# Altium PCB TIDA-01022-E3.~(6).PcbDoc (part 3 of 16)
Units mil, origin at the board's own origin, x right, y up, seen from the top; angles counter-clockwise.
Board outline 6929.13 x 11614.17 mil, 12 copper layers (L1_Top Layer, L2_GND, L3_GND, L4_Signal Layer 1, L5_GND, L6_PWR, L7_GND/PWR, L8_PWR, L9_GND/PWR, L10_Signal Layer 2, L11_GND, L12_Bottom Layer), stack 64.6 mil thick; 1733 components, 993 nets, 5987 pads, 3555 vias.

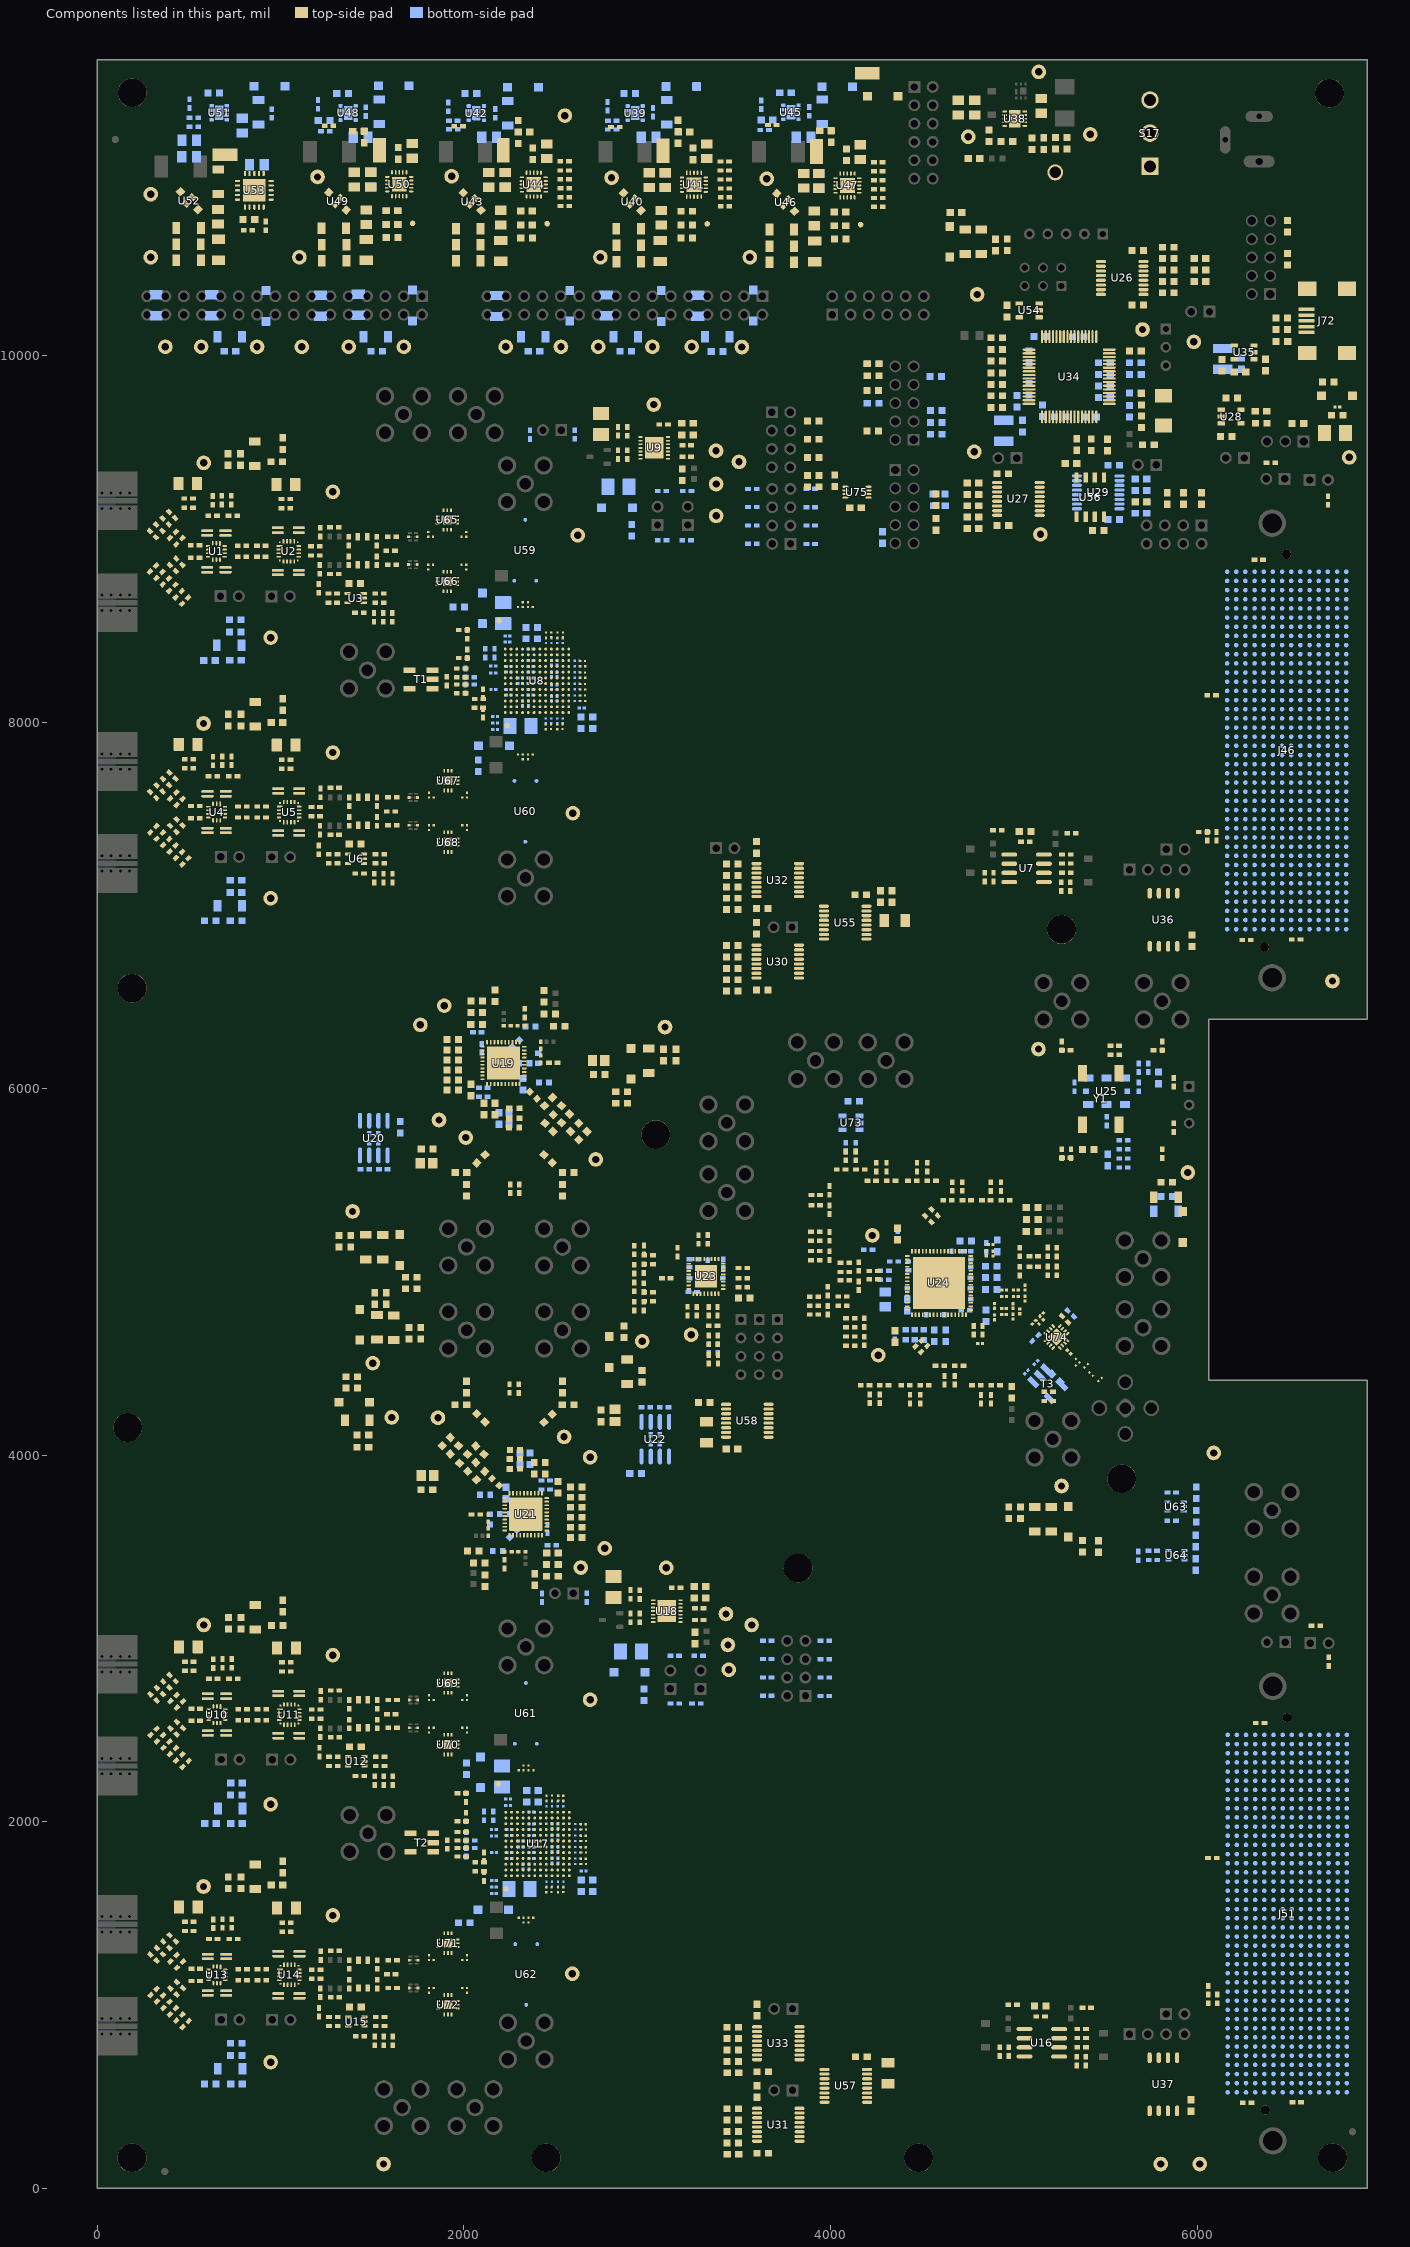
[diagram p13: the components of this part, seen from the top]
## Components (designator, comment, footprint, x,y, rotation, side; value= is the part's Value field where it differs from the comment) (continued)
R246 "CRCW04020000Z0ED" 0402#1 3103.5,4965.79 r180 top
R247 "CRCW04020000Z0ED" 0402#1 3521.5,4966.29 r0 top
R248 "CRCW04020000Z0ED" 0402#1 3521.5,5021.29 r0 top
R249 "CRCW04020000Z0ED" 0402#1 3279.5,5176.79 r90 top
R250 "CRCW04020000Z0ED" 0402#1 3330.5,5177.29 r90 top
R251 "CRCW04020000Z0ED" 0402#1 3270.5,4785.29 r270 top
R252 "CRCW04020000Z0ED" 0402#1 2982,5120.29 r90 top
R253 "CRCW04020000Z0ED" 0402#1 3335.5,4582.04 r90 bottom
R254 "CRCW04020000Z0ED" 0402#1 3007,5091.58 r180 top
R255 "CRCW04020000Z0ED" 0402#2 3105,5039.58 r180 top
R256 "CRCW04020000Z0ED" 0402#1 2981,5018.29 r270 top
R257 "CRCW04020000Z0ED" 0402#1 3384.5,4582.04 r90 bottom
R258 "CRCW0402160RJNED" 0402#1 2929.5,5015.79 r90 top
R259 "CRCW0402160RJNED" 0402#1 2929.5,5119.79 r270 top
R260 "CRCW04020000Z0ED" 0402#1 2981,4914.29 r90 top
R261 "CRCW04020000Z0ED" 0402#1 3335.75,4523.54 r90 top
R262 "CRCW04020000Z0ED" 0402#1 3007,4889.29 r180 top
R263 "CRCW04020000Z0ED" 0402#1 3335.5,4629.29 r90 top
R264 "CRCW04020000Z0ED" 0402#1 3007,4840.29 r180 top
R265 "CRCW04020000Z0ED" 0402#1 2980,4813.29 r270 top
R266 "CRCW04020000Z0ED" 0402#1 3385.75,4523.54 r90 top
R267 "CRCW0402100RFKED" 0402#1 3359.5,4707.29 r180 top
R268 "CRCW0402160RJNED" 0402#1 2929,4813.29 r90 top
R269 "CRCW0402160RJNED" 0402#1 2929,4918.29 r270 top
R270 "CRCW04020000Z0ED" 0402#1 3384.5,4629.29 r90 top
R271 "CRCW04020000Z0ED" 0402#1 3917.47,5219.44 r180 top
R272 "CRCW04020000Z0ED" 0402#1 3917.47,5064.44 r0 top
R273 "CRCW0402120RJNED" 0402#1 3993.95,5088.99 r90 top
R274 "CRCW0402120RJNED" 0402#1 3993.95,5193.99 r270 top
R275 "RC0201FR-07620RL" 0201#1 4873.47,5150.94 r0 top
R276 "CRCW0402120RJNED" 0402#1 4234.41,5004.77 r0 top
R277 "CRCW04020000Z0ED" 0402#1 4078.41,4999.77 r180 top
R278 "CRCW02010000Z0ED" 0201#1 5011.41,4866.77 r180 top
R279 "CRCW0402120RJNED" 0402#1 4234.41,4959.77 r0 top
R280 "CRCW04020000Z0ED" 0402#1 4078.41,4954.77 r180 top
R281 "RC0201JR-0751RL" 0201#1 5060.97,4854.02 r90 top
R282 "CRCW0402120RJNED" 0402#1 4154.41,5029.77 r270 top
R283 "CRCW0402120RJNED" 0402#1 4154.41,4924.77 r90 top
R284 "RC0201FR-0739KL" 0201#1 4815.97,4610.02 r0 top
R285 "CRCW04020000Z0ED" 0402#1 4078.41,5049.77 r180 top
R286 "CRCW04020000Z0ED" 0402#1 4108.01,4748.08 r180 top
R287 "CRCW04020000Z0ED" 0402#1 4108.01,4598.08 r0 top
R288 "CRCW0402120RJNED" 0402#1 4184.01,4623.08 r90 top
R289 "CRCW0402120RJNED" 0402#1 4184.01,4723.08 r270 top
R290 "CRCW02010000Z0ED" 0201#1 5011.41,4900.77 r180 top
R291 "RC0201JR-0751RL" 0201#1 5060.97,4914.02 r270 top
R292 "CRCW0402120RJNED" 0402#1 4065.03,4865.77 r0 top
R293 "CRCW04020000Z0ED" 0402#1 3909.47,4865.44 r180 top
R294 "CRCW0402120RJNED" 0402#1 4065.03,4815.77 r0 top
R295 "CRCW04020000Z0ED" 0402#1 3909.47,4815.44 r180 top
R296 "CRCW06030000Z0EA" 0603 5229.19,4421.27 r135 bottom
R297 "CRCW020149R9FKED" 0201#1 5121,4506 r45 bottom
R298 "CRCW020149R9FKED" 0201#1 4996,4756 r270 top
R299 "CRCW0402120RJNED" 0402#1 3985.03,4895.77 r270 top
R300 "CRCW0402120RJNED" 0402#1 3985.03,4790.77 r90 top
R301 "CRCW02010000Z0ED" 0201_adc 5421.69,4442.69 r135 top
R302 "CRCW02010000Z0ED" 0201#1 5109.57,4725.5 r45 top
R303 "CRCW04020000Z0ED" 0402#1 3909.47,4768.19 r180 top
R304 "CRCW04020000Z0ED" 0402#1 4433.63,4306.29 r270 top
R305 "ERJ-1GEF1000C" 0201#1 5032,4785 r270 top
R306 "CRCW04020000Z0ED" 0402#1 4488.63,4306.29 r270 top
R307 "RC0201FR-07294RL" 0201_adc 5470.19,4413.19 r225 top
R308 "RC0201FR-07294RL" 0201_adc 5394.19,4488.19 r225 top
R309 "CRCW02010000Z0ED" 0201#1 5151.27,4767.21 r225 top
R310 "CRCW04020000Z0ED" 0402#1 4621.63,4408.95 r270 top
R311 "CRCW020149R9FKED" 0201#1 5068,4454 r225 bottom
R312 "CRCW020149R9FKED" 0201#1 4996,4814 r270 top
R313 "CRCW04020000Z0ED" 0402#1 4676.63,4408.95 r270 top
R314 "CRCW04020000Z0ED" 0402#1 4820.47,4305.32 r270 top
R315 "CRCW04020000Z0ED" 0402#1 4875.47,4305.32 r270 top
R316 "CRCW04020000Z0ED" 0402#1 4717.97,5465.94 r90 top
R317 "CRCW04020000Z0ED" 0402#1 4662.97,5465.94 r90 top
R318 "CRCW04020000Z0ED" 0402#1 4929.41,5465.26 r90 top
R319 "CRCW040249R9FKED" 0402#1 5185.67,5005.53 r90 top
R320 "CRCW04020000Z0ED" 0402#1 4874.41,5465.26 r90 top
R321 "CRCW0402130RFKED" 0402#1 5234.67,5005.53 r90 top
R322 "CRCW04020000Z0ED" 0402#1 4526.62,5572.16 r90 top
R323 "CRCW04020000Z0ED" 0402#1 5809.06,6233.44 r90 top
R324 "CRCW040218R0JNED" 0402#1 5809.09,5645.89 r270 top
R325 "CRCW04020000Z0ED" 0402#1 4471.62,5572.16 r90 top
R326 "CRCW04020000Z0ED" 0402#1 5262.04,6233.44 r90 top
R327 "CRCW040218R0JNED" 0402#1 5262.08,5645.89 r270 top
R328 "CRCW0402240RJNED" 0402#1 4446.62,5497.16 r0 top
R329 "CRCW0402240RJNED" 0402#1 4551.62,5497.16 r180 top
R330 "CRCW0402240RJNED" 0402#1 4849.41,5390.26 r0 top
R331 "CRCW0402240RJNED" 0402#1 4954.41,5390.26 r180 top
R332 "CRCW0402240RJNED" 0402#1 4638,5390.5 r0 top
R333 "CRCW0402240RJNED" 0402#1 4743,5390.5 r180 top
R334 "CRCW0402240RJNED" 0402#1 4900.48,4381.19 r180 top
R335 "CRCW0402240RJNED" 0402#1 4795.48,4381.19 r0 top
R336 "CRCW0402240RJNED" 0402#1 4701.63,4488.95 r180 top
R337 "CRCW0402240RJNED" 0402#1 4596.63,4488.95 r0 top
R338 "CRCW0402240RJNED" 0402#1 4512.25,4382.29 r180 top
R339 "CRCW0402240RJNED" 0402#1 4408.63,4382.29 r0 top
R340 "CRCW0402130RFKED" 0402#1 5234.67,5108.53 r270 top
R341 "CRCW040249R9FKED" 0402#1 5185.67,5109.24 r270 top
R342 "CRCW040220R0FKED" 0402#1 4479.64,4610.21 r45 top
R343 "CRCW04020000Z0ED" 0402#1 4212.97,4308.02 r270 top
R344 "CRCW0402100RFKED" 0402#1 5311.63,5645.1 r90 top
R345 "CRCW040220R0FKED" 0402#1 4510.77,4580.16 r45 top
R346 "CRCW04020000Z0ED" 0402#1 4267.97,4308.02 r270 top
R347 "CRCW0402220RJNED" 0402#1 4292.44,4382.29 r180 top
R348 "CRCW0402220RJNED" 0402#1 4187.97,4382.29 r0 top
R349 "CRCW040220R0FKED" 0402#1 4567.97,5324.02 r315 top
R350 "CRCW04020000Z0ED" 0402#1 4304.86,5571.99 r90 top
R351 "RC0603FR-0782RL" 0603 5406.13,5668.6 r180 top
R352 "CRCW04021K20JNED" 0402#1 5330.97,6009.84 r90 bottom
R353 "CRCW04021K20JNED" 0402#1 5680.97,6009.84 r90 bottom
R354 "CRCW040220R0FKED" 0402#1 4532.97,5289.02 r315 top
R355 "CRCW04020000Z0ED" 0402#1 4249.86,5571.99 r90 top
R356 "CRCW04020000Z0ED" 0402#1 5285.66,6209.82 r180 top
R357 "CRCW04020000Z0ED" 0402#1 5785.44,6209.82 r0 top
R358 "CRCW04021K20JNED" 0402#1 5505.97,5822.49 r90 bottom
R359 "CRCW04020000Z0ED" 0402#1 5550.5,6233.95 r180 top
R360 "CRCW04020000Z0ED" 0402#1 4137.62,5633.5 r90 top
R361 "CRCW04020000Z0ED" 0402#1 4082.62,5633.5 r90 top
R362 "CRCW0402240RJNED" 0402#1 4057.62,5558.5 r0 top
R363 "CRCW0402240RJNED" 0402#1 4162.62,5558.5 r180 top
R364 "CRCW0402240RJNED" 0402#1 3994.28,5339.5 r90 top
R365 "CRCW0402240RJNED" 0402#1 3994.28,5444.5 r270 top
R366 "CRCW0402220RJNED" 0402#1 4224.86,5496.99 r0 top
R367 "CRCW0402220RJNED" 0402#1 4329.86,5496.99 r180 top
R368 "ERJ-2RKF1002X" 0402#1 4448.66,5008.62 r180 bottom
R369 "CRCW040247R0JNED" 0402#1 4294.09,4956.94 r0 bottom
R370 "CRCW0603750RFKEA" 0603 5099.49,5352.39 r0 top
R371 "CRCW0603750RFKEA" 0603 5101.03,5286.39 r0 top
R372 "CRCW0603750RFKEA" 0603 4988.39,4342.97 r270 top
R373 "CRCW0603750RFKEA" 0603 5099.47,5220.14 r0 top
R374 "CRCW06030000Z0EA" 0603 4576,9078.5 r270 top
R375 "CRCW06030000Z0EA" 0603 6015.28,10528.12 r0 top
R376 "CRCW06030000Z0EA" 0603 4593.57,9180.1 r180 bottom
R377 "CRCW06030000Z0EA" 0603 6015.28,10466.05 r0 top
R378 "CRCW06030000Z0EA" 0603 4592,9244 r180 bottom
R379 "CRCW06030000Z0EA" 0603 6015.5,10403 r0 top
R380 "CRCW060310K0JNEA" 0603 6549.5,9629.5 r0 top
R381 "CRCW060310K0JNEA" 0603 6024,9220 r270 top
R382 "CRCW060310K0JNEA" 0603 6348,9696 r0 top
R383 "CRCW060310K0JNEA" 0603 5925,9220 r270 top
R384 "CRCW060310K0JNEA" 0603 5837,9220 r270 top
R385 "CRCW060310K0JNEA" 0603 5694.63,9202.01 r0 top
R386 "CRCW06030000Z0EA" 0603 3199.95,11220.04 r0 top
R387 "CRCW06030000Z0EA" 0603 3168.46,11251.53 r270 top
R388 "CRCW06030000Z0EA" 0603 2327.5,11219.5 r0 top
R389 "CRCW06030000Z0EA" 0603 2296,11250.99 r270 top
R390 "CRCW04020000Z0ED" 0402#1 4137.62,5680.75 r90 bottom
R391 "CRCW04020000Z0ED" 0402#1 4082.62,5680.75 r90 bottom
R392 "CRCW02010000Z0ED" 0201_ADC 5348,4497.63 r225 top
R393 "CRCW040233K0JNED" 0402#1 5189.54,4296.24 r180 top
R394 "RC0603FR-07100RL" 0603 5842.35,10528.12 r0 top
R395 "ERJ-1GN0R00C" 0201#1 5151.27,4748.84 r315 top
R396 "RC0603FR-07100RL" 0603 5842.35,10466.12 r0 top
R397 "CRCW0402100KFKED" 0402#1 5189.73,4347 r180 top
R398 "RC0603FR-07100RL" 0603 5842.35,10404.12 r0 top
R399 "ERJ-1GN0R00C" 0201#1 5127.94,4725.5 r315 top
R400 "RC0603FR-07100RL" 0603 5842.35,10342.12 r0 top
R401 "CRCW02010000Z0ED" 0201_ADC 5348,4516 r135 top
R402 "RC0603FR-07100RL" 0603 4776.82,9118.2 r180 top
R403 "CRCW06030000Z0EA" 0603 3311.29,4288.29 r0 top
R404 "RC0603FR-07100RL" 0603 5675.5,10276 r0 top
R405 "RC0603FR-07100RL" 0603 4776.82,9180.2 r180 top
R406 "CRCW060310K0JNEA" 0603 3906,9346 r180 top
R407 "RC0603FR-07100RL" 0603 4776.82,9242.2 r180 top
R408 "CRCW06030000Z0EA" 0603 3906,9284 r180 top
R409 "RC0603FR-07100RL" 0603 4776.82,9304.2 r180 top
R410 "CRCW06030000Z0EA" 0603 4023,9316 r90 top
R411 "RC0603FR-07100RL" 0603 4939.82,9355 r180 top
R412 "CRCW04020000Z0ED" 0402#1 4204.66,5120.41 r180 bottom
R413 "CRCW04020000Z0ED" 0402#1 6032.2,7400.52 r0 top
R414 "CRCW04020000Z0ED" 0402#1 6060,1081.05 r90 top
R415 "CRCW06030000Z0EA" 0603 2296,11188 r90 top
R416 "RC0603FR-07100RL" 0603 6349,9630 r0 top
R417 "CRCW06030000Z0EA" 0603 4003.63,11194.81 r90 top
R418 "CRCW06030000Z0EA" 0603 3972.13,11226.3 r180 top
R419 "CRCW06030000Z0EA" 0603 1455.74,11191.81 r90 top
R420 "RC0603FR-07100RL" 0603 6159.05,9557.28 r0 top
R421 "RC0603FR-07100RL" 0603 5693.82,9201.2 r0 bottom
R422 "CRCW06030000Z0EA" 0603 1424.25,11223.3 r180 top
R423 "RC0603FR-07100RL" 0603 5693.82,9263.2 r0 bottom
R424 "RC0603FR-07100RL" 0603 5693.82,9325.2 r0 bottom
R425 "RC0603FR-07100RL" 0603 5544.82,9401 r0 bottom
R426 "CRCW060333R0JNEA" 0603 4574,9886 r180 bottom
R427 "CRCW060333R0JNEA" 0603 4576,9699 r180 bottom
R428 "CRCW060333R0JNEA" 0603 4577,9634 r180 bottom
R429 "CRCW060310K0JNEA" 0603 3906,9643 r180 top
R430 "CRCW060310K0JNEA" 0603 3906,9543 r180 top
R431 "CRCW060310K0JNEA" 0603 3906,9443 r180 top
R432 "CRCW06031K00FKEA" 0603 3463.47,6594.22 r180 top
R433 "CRCW06031K00FKEA" 0603 3466.8,248.22 r180 top
R434 "CRCW06031K00FKEA" 0603 3463.47,6656.22 r180 top
R435 "CRCW06031K00FKEA" 0603 3466.8,310.22 r180 top
R436 "CRCW06031K00FKEA" 0603 3463.47,6718.22 r180 top
R437 "CRCW06031K00FKEA" 0603 3466.8,372.22 r180 top
R438 "CRCW06031K00FKEA" 0603 3463.47,6780.22 r180 top
R439 "CRCW06031K00FKEA" 0603 3466.8,434.22 r180 top
R440 "RC0603FR-07100RL" 0603 3595.07,6874.73 r270 top
R441 "RC0603FR-07100RL" 0603 3598.4,528.73 r270 top
R442 "CRCW06030000Z0EA" 0603 4334.36,7048 r90 top
R443 "CRCW06030000Z0EA" 0603 4271.61,7047.81 r90 top
R445 "RC0603FR-07100RL" 0603 4906.31,10033 r180 top
R447 "RC0603FR-07100RL" 0603 4906.31,9969 r180 top
R449 "RC0603FR-07100RL" 0603 4906.31,9780 r180 top
R451 "RC0603FR-07100RL" 0603 4906.31,9905 r180 top
R452 "RC0603FR-07100RL" 0603 4906.31,9842 r180 top
R454 "RC0603FR-07100RL" 0603 4906.31,9717 r180 top
R455 "CRCW06031K00FKEA" 0603 3463.47,7038.93 r180 top
R456 "CRCW06031K00FKEA" 0603 3466.8,692.93 r180 top
R458 "CRCW06031K00FKEA" 0603 3463.47,7100.93 r180 top
R459 "CRCW06031K00FKEA" 0603 3466.8,754.93 r180 top
R461 "CRCW06031K00FKEA" 0603 3463.47,7162.93 r180 top
R462 "CRCW06031K00FKEA" 0603 3466.8,816.93 r180 top
R464 "CRCW06031K00FKEA" 0603 3463.47,7224.93 r180 top
R465 "CRCW06031K00FKEA" 0603 3466.8,878.93 r180 top
R467 "RC0603FR-07100RL" 0603 3595.43,7316.26 r270 top
R468 "RC0603FR-07100RL" 0603 3598.4,973.44 r270 top
R469 "CRCW0603270RJNEA" 0603 5733.88,9512.97 r180 top
R470 "CRCW06030000Z0EA" 0603 6462.21,10077.06 r180 top
R472 "CRCW060310R0FKEAHP" 0603 6461.74,10140.92 r180 top
R473 "CRCW04024K99FKED" 0402#1 6402.4,9415.54 r0 top
R474 "CRCW04020000Z0ED" 0402#1 6539.48,6813.63 r0 top
R475 "CRCW0402100RJNED" 0402#1 6713.79,9208.78 r90 top
R476 "CRCW0402100RJNED" 0402#1 6336.11,8886.01 r0 top
R477 "CRCW04020000Z0ED" 0402#1 6269.11,6811.01 r0 top
R478 "CRCW04024K99FKED" 0402#1 6647.6,3069.74 r0 top
R479 "CRCW04020000Z0ED" 0402#1 6543.13,470.43 r0 top
R480 "CRCW0402100RJNED" 0402#1 6717.12,2874.04 r90 top
R481 "CRCW0402100RJNED" 0402#1 6343.13,2539.43 r0 top
R482 "CRCW04020000Z0ED" 0402#1 6272.75,467.81 r0 top
R483 "CRCW04022K00FKED" 0402#1 678.91,9210.99 r270 top
R484 "CRCW06031M00FKEA" 0603 5258.82,11188.8 r0 top
R485 "CRCW06031K00FKEA" 0603 4782.31,11074.8 r180 top
R486 "CRCW060310K0FKEA" 0603 5162.82,11155.8 r90 top
R487 "CRCW060345K3FKEA" 0603 4863.82,11198.8 r90 top
R488 "CRCW0603100KFKEA" 0603 4961.82,11167.8 r180 top
R489 "CRCW0402100KFKED" 0402#1 2826.31,11246.7 r180 top
R490 "CRCW040211K0FKED" 0402#1 2808.66,11281.33 r0 bottom
R491 "CRCW040213K7FKED" 0402#1 2808.45,11233.09 r0 bottom
R492 "CRCW04028K06FKED" 0402#1 2782.75,11359.93 r270 bottom
R493 "CRCW060310K0FKEA" 0603 3215.46,10640.06 r0 top
R494 "CRCW06030000Z0EA" 0603 3214.86,10786.68 r180 top
R495 "CRCW04020000Z0ED" 0402#1 3422.92,11058.68 r180 top
R496 "CRCW04020000Z0ED" 0402#1 3422.92,11008.68 r180 top
R497 "CRCW04020000Z0ED" 0402#1 3422.92,10959.68 r180 top
R498 "CRCW04020000Z0ED" 0402#1 3423.92,10910.68 r180 top
R499 "CRCW04020000Z0ED" 0402#1 3423.92,10862.68 r180 top
R500 "CRCW04020000Z0ED" 0402#1 3423.92,10814.68 r180 top
R501 "CRCW04023K24FKED" 0402#1 1941.66,11281.28 r0 bottom
R502 "CRCW04026K34FKED" 0402#1 1941.76,11233.28 r180 bottom
R503 "CRCW0402100KFKED" 0402#1 1970.38,11250.87 r180 top
R504 "CRCW04029K09FKED" 0402#1 1913.41,11356.31 r270 bottom
R505 "CRCW060310K0FKEA" 0603 2341.63,10640.92 r0 top
R506 "CRCW06030000Z0EA" 0603 2341.03,10787.54 r180 top
R507 "CRCW04020000Z0ED" 0402#1 2549.09,11059.54 r180 top
R508 "CRCW04020000Z0ED" 0402#1 2549.09,11009.54 r180 top
R509 "CRCW04020000Z0ED" 0402#1 2549.09,10960.54 r180 top
R510 "CRCW04020000Z0ED" 0402#1 2550.09,10911.54 r180 top
R511 "CRCW04020000Z0ED" 0402#1 2550.09,10863.54 r180 top
R512 "CRCW04020000Z0ED" 0402#1 2550.09,10815.54 r180 top
R513 "CRCW0402100KFKED" 0402#1 3681.65,11257.14 r180 top
R514 "CRCW060334K8FKEA" 0603 3652.67,11285.46 r0 bottom
R515 "CRCW040238K3FKED" 0402#1 3640.49,11229.79 r0 bottom
R516 "CRCW040211K3FKED" 0402#1 3622.32,11367.8 r270 bottom
R517 "CRCW060310K0FKEA" 0603 4052.43,10636.06 r0 top
R518 "CRCW06030000Z0EA" 0603 4051.83,10782.67 r180 top
R519 "CRCW04020000Z0ED" 0402#1 4259.9,11054.67 r180 top
R520 "CRCW04020000Z0ED" 0402#1 4259.9,11004.67 r180 top
R521 "CRCW04020000Z0ED" 0402#1 4259.9,10955.67 r180 top
R522 "CRCW04020000Z0ED" 0402#1 4260.9,10906.67 r180 top
R523 "CRCW04020000Z0ED" 0402#1 4260.9,10858.67 r180 top
R524 "CRCW04020000Z0ED" 0402#1 4260.9,10810.67 r180 top
R525 "CRCW0402100KFKED" 0402#1 1263.38,11252.87 r180 top
R526 "CRCW060324K9FKEA" 0603 1236.87,11281.5 r0 bottom
R527 "CRCW040227K4FKED" 0402#1 1243.66,11223.81 r0 bottom
R528 "CRCW040211K3FKED" 0402#1 1203.63,11369.52 r270 bottom
R529 "CRCW060310K0FKEA" 0603 1607.76,10642.79 r0 top
R530 "CRCW06030000Z0EA" 0603 1607.16,10789.4 r180 top
R531 "CRCW060324K3FKEA" 0603 1607.16,10714.4 r180 bottom
R532 "CRCW060311K5FKEA" 0603 1607.16,10789.4 r0 bottom
R533 "CRCW040219K6FKED" 0402#1 526,11247.92 r0 bottom
R534 "CRCW040228K7FKED" 0402#1 526,11296.92 r0 bottom
R535 "CRCW04029K09FKED" 0402#1 502.75,11373.95 r270 bottom
R536 "CRCW0402118KFKED" 0402#1 821.5,10682.57 r180 top
R537 "CRCW0402105KFKED" 0402#1 918.5,10706.57 r270 top
R539 "CRCW060310R0FKEAHP" 0603 6461.74,10204.92 r180 top
R541 "RC1206FR-0710KL" 1206 4350,6917 r0 top
R542 "CRCW060312K0JNEA" 0603 5493.88,9832.97 r180 bottom
R543 "CRCW06031K00FKEA" 0603 5662.88,10024.97 r180 top
R544 "CRCW060310K0JNEA" 0603 5510.88,9511.97 r90 top
R545 "CRCW060310K0JNEA" 0603 5311.38,9410.97 r180 top
R546 "CRCW060310K0JNEA" 0603 5421.88,9512.97 r90 top
R547 "CRCW06032K20JNEA" 0603 5342.88,9513.97 r90 top
R548 "RC1206FR-0710KL" 1206 4313.15,628.52 r90 top
R549 "CRCW06031K00FKEA" 0603 4906.81,10097 r180 top
R550 "RC1206FR-0710KL" 1206 3323.18,4126.15 r270 top
R551 "CRCW02010000Z0ED" 0201_adc 2362.26,8627.3 r180 top
R552 "CRCW02010000Z0ED" 0201_adc 2308.27,8627.43 r0 top
R553 "ERJ-2RKF1001X" 0402#1 411.92,9021.28 r225 top
R554 "ERJ-2RKF1001X" 0402#1 411.92,8839.7 r135 top
R555 "FC0402E50R0BTBST1" 0402#1 478.3,8662.3 r45 top
R556 "CRCW04022K00FKED" 0402#1 1508.91,8570.79 r270 top
R557 "CRCW04022K00FKED" 0402#1 1558.91,8570.79 r90 top
R558 "CRCW04022K00FKED" 0402#1 1607.91,8570.79 r90 top
R559 "CRCW04022K00FKED" 0402#1 680.71,7788.86 r270 top
R560 "CRCW02010000Z0ED" 0201_adc 2308.09,7822.89 r0 top
R561 "CRCW02010000Z0ED" 0201_adc 2361.99,7822.92 r180 top
R562 "ERJ-2RKF1001X" 0402#1 413.72,7599.15 r225 top
R563 "ERJ-2RKF1001X" 0402#1 413.72,7417.58 r135 top
R564 "FC0402E50R0BTBST1" 0402#1 480.09,7240.17 r45 top
R565 "CRCW04022K00FKED" 0402#1 1510.71,7148.66 r270 top
R566 "CRCW04022K00FKED" 0402#1 1560.71,7148.66 r90 top
R567 "CRCW04022K00FKED" 0402#1 1609.71,7148.66 r90 top
R568 "CRCW04022K00FKED" 0402#1 682.23,2864.63 r270 top
R569 "CRCW02010000Z0ED" 0201_adc 2365.5,2281.21 r180 top
R570 "CRCW02010000Z0ED" 0201_adc 2311.6,2281.43 r0 top
R571 "ERJ-2RKF1001X" 0402#1 415.24,2674.91 r225 top
R572 "ERJ-2RKF1001X" 0402#1 415.24,2493.34 r135 top
R573 "FC0402E50R0BTBST1" 0402#1 481.61,2315.93 r45 top
R574 "CRCW04022K00FKED" 0402#1 1512.23,2224.42 r270 top
R575 "CRCW04022K00FKED" 0402#1 1562.23,2224.42 r90 top
R576 "CRCW04022K00FKED" 0402#1 1611.23,2224.42 r90 top
R577 "CRCW04022K00FKED" 0402#1 682.3,1445.29 r270 top
R578 "CRCW02010000Z0ED" 0201_adc 2311.51,1476.99 r0 top
R579 "CRCW02010000Z0ED" 0201_adc 2365.39,1476.87 r180 top
R580 "ERJ-2RKF1001X" 0402#1 415.31,1255.58 r225 top
R581 "ERJ-2RKF1001X" 0402#1 415.31,1074.01 r135 top
R582 "FC0402E50R0BTBST1" 0402#1 481.69,896.6 r45 top
R583 "CRCW04022K00FKED" 0402#1 1512.3,805.09 r270 top
R584 "CRCW04022K00FKED" 0402#1 1562.3,805.09 r90 top
R585 "CRCW04022K00FKED" 0402#1 1611.3,805.09 r90 top
R586 "CRCW04020000Z0ED" 0402#1 6079.11,8146.01 r0 top
R587 "CRCW04020000Z0ED" 0402#1 6105.11,7377.01 r90 top
R588 "CRCW04020000Z0ED" 0402#1 5861,3643 r0 bottom
R589 "CRCW04020000Z0ED" 0402#1 6108.75,1033.81 r90 top
R590 "CRCW04020000Z0ED" 0402#1 6082.75,1802.81 r180 top
R591 "RC0603FR-07100RL" 0603 5017,9750 r270 bottom
R592 "CRCW02010000Z0ED" 0201_adc 2349.27,8640.3 r270 top
R593 "CRCW06030000Z0EA" 0603 4283,9007 r90 bottom
R594 "CRCW06030000Z0EA" 0603 6492.27,10704.39 r270 top
R595 "CRCW06030000Z0EA" 0603 4574.57,9212.6 r270 top
R596 "CRCW06030000Z0EA" 0603 6492.24,10524.59 r270 top
R597 "CRCW060333R0JNEA" 0603 4232,9889 r180 top
R598 "CRCW06030000Z0EA" 0603 4232,9955 r180 top
R599 "CRCW060333R0JNEA" 0603 4232,9955 r180 bottom
R600 "CRCW06030000Z0EA" 0603 4232,9739 r0 bottom
R601 "CRCW060333R0JNEA" 0603 4230.5,9588 r0 top
R602 "CRCW060333R0JNEA" 0603 4230.5,9809 r0 top
R603 "CRCW060333R0JNEA" 0603 4577,9570 r180 bottom
R604 "CRCW02010000Z0ED" 0201_adc 2320.77,8640.31 r270 top
R605 "CRCW02010000Z0ED" 0201_adc 2321.08,7809.9 r90 top
R606 "CRCW02010000Z0ED" 0201_adc 2348.98,7809.92 r90 top
R607 "CRCW02010000Z0ED" 0201_adc 2352.58,2293.94 r270 top
R608 "CRCW02010000Z0ED" 0201_adc 2324.18,2294.27 r270 top
R609 "CRCW02010000Z0ED" 0201_adc 2324.51,1462.99 r90 top
R610 "CRCW02010000Z0ED" 0201_adc 2352.41,1464.02 r90 top
R614 "CRCW12060000Z0EA" 1206 3070.64,10569.99 r270 top
R618 "CRCW12060000Z0EA" 1206 2199.9,10570.34 r270 top
R622 "CRCW12060000Z0EA" 1206 3913.49,10567.63 r270 top
R626 "CRCW12060000Z0EA" 1206 1467.35,10575.83 r270 top
R630 "CRCW12060000Z0EA" 1206 661,10577 r270 top
R631 "RT0603DRE0710KL" 0603 5991.9,3531.82 r90 bottom
R632 "RT0603DRE0710KL" 0603 5991.9,3403.82 r270 bottom
R633 "CRCW04020000Z0ED" 0402#1 6055.82,7376.9 r90 top
R634 "RT0603DRE0710KL" 0603 5994.9,3666.82 r270 bottom
R635 "RT0603DRE0710KL" 0603 5994.9,3794.82 r90 bottom
R636 "CRCW04020000Z0ED" 0402#1 5759,3428 r180 bottom
R637 "CRCW04020000Z0ED" 0402#1 6060,1033.81 r90 top
R638 "CRCW04020000Z0ED" 0402_FILTER 1721.38,9011 r0 top
R639 "CRCW04020000Z0ED" 0402_FILTER 1721.38,8859 r0 top
R640 "CRCW04020000Z0ED" 0402_FILTER 1723.18,7588.87 r0 top
R641 "CRCW04020000Z0ED" 0402_FILTER 1723.18,7436.87 r0 top
R642 "CRCW04020000Z0ED" 0402_FILTER 1724.69,2664.64 r0 top
R643 "CRCW04020000Z0ED" 0402_FILTER 1724.69,2512.64 r0 top
R644 "CRCW04020000Z0ED" 0402_FILTER 1724.77,1245.3 r0 top
R645 "CRCW04020000Z0ED" 0402_FILTER 1724.77,1093.3 r0 top
R646 "CRCW02010000Z0ED" 0201_adc 1805.01,9023.67 r90 top
R647 "CRCW02010000Z0ED" 0201_adc 2012.83,9023.67 r90 top
R648 "CRCW02010000Z0ED" 0201_adc 1818,9010.68 r0 top
R649 "CRCW02010000Z0ED" 0201_adc 1999.84,9010.68 r0 top
R650 "CRCW02010000Z0ED" 0201_adc 1805.01,8845.71 r270 top
R651 "CRCW02010000Z0ED" 0201_adc 2012.83,8845.71 r270 top
R652 "CRCW02010000Z0ED" 0201_adc 1818,8858.7 r0 top
R653 "CRCW02010000Z0ED" 0201_adc 1999.84,8858.7 r0 top
R654 "CRCW02010000Z0ED" 0201_adc 2016.45,7601.59 r90 top
R655 "CRCW02010000Z0ED" 0201_adc 1808.63,7601.59 r90 top
R656 "CRCW02010000Z0ED" 0201_adc 1821.62,7588.6 r0 top
R657 "CRCW02010000Z0ED" 0201_adc 2003.46,7588.6 r0 top
R658 "CRCW02010000Z0ED" 0201_adc 1808.63,7423.63 r270 top
R659 "CRCW02010000Z0ED" 0201_adc 2016.45,7423.63 r270 top
R660 "CRCW02010000Z0ED" 0201_adc 1821.62,7436.62 r0 top
R661 "CRCW02010000Z0ED" 0201_adc 2003.46,7436.62 r0 top
R662 "CRCW02010000Z0ED" 0201_adc 2016.45,2677.99 r90 top
R663 "CRCW02010000Z0ED" 0201_adc 1808.63,2677.99 r90 top
R664 "CRCW02010000Z0ED" 0201_adc 1821.62,2665 r0 top
R665 "CRCW02010000Z0ED" 0201_adc 2003.46,2665 r0 top
R666 "CRCW02010000Z0ED" 0201_adc 1808.63,2500.03 r270 top
R667 "CRCW02010000Z0ED" 0201_adc 2016.45,2500.03 r270 top
R668 "CRCW02010000Z0ED" 0201_adc 1821.62,2513.02 r0 top
R669 "CRCW02010000Z0ED" 0201_adc 2003.46,2513.02 r0 top
R670 "CRCW02010000Z0ED" 0201_adc 2016.45,1258.89 r90 top
R671 "CRCW02010000Z0ED" 0201_adc 1808.63,1258.89 r90 top
R672 "CRCW02010000Z0ED" 0201_adc 1821.62,1245.9 r0 top
R673 "CRCW02010000Z0ED" 0201_adc 2003.46,1245.9 r0 top
R674 "CRCW02010000Z0ED" 0201_adc 1808.63,1080.93 r270 top
R675 "CRCW02010000Z0ED" 0201_adc 2016.45,1080.93 r270 top
R676 "CRCW02010000Z0ED" 0201_adc 1821.62,1093.92 r0 top
R677 "CRCW02010000Z0ED" 0201_adc 2003.46,1093.92 r0 top
RMPCLK1 "5002" Keystone5002 1892.22,6452.81 r135 top
RMPCLK2 "5002" Keystone5002 2637.47,3387.09 r225 top
RMPDIR1 "5002" Keystone5002 1762.22,6347.81 r135 top
RMPDIR2 "5002" Keystone5002 2767.47,3492.09 r225 top
S1 "1648-440-AL" TCBS-6-01 188.67,166.9 r180 bottom
S2 "1648-440-AL" TCBS-6-01 6739,166.9 r180 bottom
S3 "1648-440-AL" TCBS-6-01 2448,166.9 r180 bottom
S4 "1648-440-AL" TCBS-6-01 190,11433.07 r180 bottom
S5 "1648-440-AL" TCBS-6-01 166,4152 r90 bottom
S6 "1648-440-AL" TCBS-6-01 4479.67,166.9 r180 bottom
S7 "1648-440-AL" TCBS-6-01 5589,3872 r90 bottom
S8 "1648-440-AL" TCBS-6-01 3823,3384 r90 bottom
S9 "1648-440-AL" TCBS-6-01 3046,5749 r180 bottom
S10 "1648-440-AL" TCBS-6-01 5260,6869 r180 bottom
S11 "1648-440-AL" TCBS-6-01 6721.68,11430.97 r180 bottom
S12 "1648-440-AL" TCBS-6-01 189,6548 r180 bottom
S17 "L101011MS02Q" "SW_ L101011MS02Q" 5855,11213.07 r180 top
SYNC1 "5002" Keystone5002 4227.97,5199.02 r0 top
T1 "TC1-1-43X+" MNC_AT1521 1766.39,8233 r270 top
T2 "TC1-1-43X+" MNC_AT1521 1769.72,1887 r270 top
T3 "TC1-1-13M+" TFMR_5_150x150_50 5185.19,4389.27 r315 bottom
TP1 "5002" Keystone5002 3500.46,9419.35 r0 top
TP2 "5002" Keystone5002 3035.1,9732.03 r0 top
TP3 "5002" Keystone5002 3374.9,9479.89 r0 top
TP4 "TP-025-SMT" PROBE_POINT_30PAD 2192.32,8553.24 r90 top
TP5 "TP-025-SMT" PROBE_POINT_30PAD 2235.17,7980.92 r90 top
TP6 "5000" Keystone5000 2620.24,9019.18 r90 bottom
TP7 "5002" Keystone5002 3569.21,3074 r0 top
TP8 "5002" Keystone5002 3103.43,3386.26 r0 top
TP9 "5002" Keystone5002 3429.3,3134.12 r0 top
TP10 "TP-025-SMT" PROBE_POINT_30PAD 2186.26,2206.8 r90 top
TP11 "TP-025-SMT" PROBE_POINT_30PAD 2229.11,1634.01 r90 top
TP12 "5000" Keystone5000 2688,2665.77 r90 top
TP13 "5000" Keystone5000 5701.87,10141.47 r90 top
TP14 "5000" Keystone5000 4784,9475 r270 top
TP15 "5001" Keystone5001 1371,10047 r90 top
TP16 "5001" Keystone5001 3242,10047 r90 top
TP17 "5000" Keystone5000 5416.86,11206 r270 top
TP18 "5000" Keystone5000 4750.82,11192.8 r270 top
TP19 "5012" Keystone5012 5225.82,10998.8 r270 top
TP20 "5001" Keystone5001 5136.07,11547 r270 top
TP21 "5000" Keystone5000 2805,10970 r180 top
TP22 "5000" Keystone5000 3028,10047 r270 top
TP23 "5000" Keystone5000 6830,9444 r0 top
TP24 "5000" Keystone5000 2972,4622 r0 top
TP25 "5000" Keystone5000 1932.43,10978 r180 top
TP26 "5000" Keystone5000 2529,10047 r270 top
TP27 "5001" Keystone5001 2732,10047 r90 top
TP28 "5001" Keystone5001 1115,10047 r90 top
TP29 "5001" Keystone5001 566,10047 r90 top
TP30 "5001" Keystone5001 2228,10047 r90 top
TP31 "5000" Keystone5000 1392,5330 r90 top
TP32 "5000" Keystone5000 3652,10964 r180 top
TP33 "5000" Keystone5000 3516,10046 r90 top
TP34 "5000" Keystone5000 3096.68,6335.9 r270 top
TP35 "5000" Keystone5000 1502.26,4502.4 r270 top
TP36 "5000" Keystone5000 1605.43,4206.08 r180 top
TP37 "5000" Keystone5000 5260.23,3832.01 r90 top
TP38 "5000" Keystone5000 5949.23,5542.49 r270 top
TP39 "5000" Keystone5000 4799.4,10332.82 r0 top
TP42 "5000" Keystone5000 1201,10974 r90 top
TP43 "5000" Keystone5000 1672,10047 r90 top
TP46 "5000" Keystone5000 580,9414 r90 top
TP47 "5000" Keystone5000 580,3074 r90 top
TP48 "5000" Keystone5000 579,7992 r90 top
TP49 "5000" Keystone5000 579,1647 r90 top
TP50 "5001" Keystone5001 371,10047 r90 top
TP51 "5001" Keystone5001 1284.6,9255.77 r90 top
TP52 "5001" Keystone5001 1284.6,7833.64 r90 top
TP53 "5001" Keystone5001 1284.6,2909.41 r90 top
TP55 "5000" Keystone5000 945.2,8460.6 r90 top
TP57 "5000" Keystone5000 945.2,7038.47 r90 top
TP58 "5000" Keystone5000 871,10047 r90 top
TP59 "5000" Keystone5000 290.71,10880 r0 top
TP61 "5000" Keystone5000 945,2096 r90 top
TP63 "5000" Keystone5000 945,689 r90 top
TP64 "5001" Keystone5001 1284.6,1489.13 r90 top
TP65 "5001" Keystone5001 2594,7503 r90 top
TP66 "5001" Keystone5001 2591,1171 r90 top
TP67 "5001" Keystone5001 1561,133 r90 top
TP68 "5001" Keystone5001 5801,133 r90 top
TP69 "5001" Keystone5001 5982,10074 r90 top
TP70 "5001" Keystone5001 5145,9024 r90 top
TP71 "5001" Keystone5001 6090,4012.46 r90 top
TP72 "5001" Keystone5001 4260,4546 r90 top
TP73 "5001" Keystone5001 2010,5733 r90 top
TP74 "5001" Keystone5001 2546,4100 r90 top
TP75 "5001" Keystone5001 3239,4657 r90 top
TP76 "5001" Keystone5001 5134,6216 r90 top
TP77 "5015" Testpoint_Keystone_Miniature 4200,11540 r180 top
TP78 "TP-025-SMT" PROBE_POINT_30PAD 2453.2,10718.86 r180 top
TP79 "TP-025-SMT" PROBE_POINT_30PAD 4164,10714 r180 top
TP80 "TP-025-SMT" PROBE_POINT_30PAD 1719.33,10720.73 r180 top
TP81 "TP-025-SMT" PROBE_POINT_30PAD 3327.03,10718.01 r90 top
TP82 "5015" Testpoint_Keystone_Miniature 3085,11117 r90 top
TP83 "5015" Testpoint_Keystone_Miniature 2214,11119 r90 top
TP84 "5015" Testpoint_Keystone_Miniature 3924,11113 r90 top
TP85 "5015" Testpoint_Keystone_Miniature 1538.24,11120 r270 top
TP86 "5015" Testpoint_Keystone_Miniature 695.84,11094.82 r180 top
TP87 "5001" Keystone5001 291,10536 r90 top
TP88 "5001" Keystone5001 1102,10536 r90 top
TP89 "5001" Keystone5001 2744.24,10536 r90 top
TP90 "5001" Keystone5001 3559.7,10536 r90 top
TP91 "5001" Keystone5001 2550.35,11308.59 r90 top
U1 "LMH5401IRMSR" RMS0014A 648.91,8930.99 r270 top
U2 "LMH6401IRMZR" RMZ0016A 1044.09,8931.26 r0 top
U3 "OPA376AIDCKT" DCK0005A_N#1 1854.09,8676.26 r180 top
U4 "LMH5401IRMSR" RMS0014A 650.71,7508.86 r270 top
U5 "LMH6401IRMZR" RMZ0016A 1045.89,7509.13 r0 top
U6 "OPA376AIDCKT" DCK0005A_N#2 1410.89,7254.13 r180 top
U7 "LMC6762AIMX" M08A_N 5069.21,7202.18 r0 top
U8 "ADC12DJ3200AAVR" AAV0144A 2398.17,8225.09 r0 top
U9 "LM95233CISD" SDA14B 3038.17,9495.58 r0 top
U10 "LMH5401IRMSR" RMS0014A 652.23,2584.63 r270 top
U11 "LMH6401IRMZR" RMZ0016A 1047.41,2584.9 r0 top
U12 "OPA376AIDCKT" DCK0005A_N#2 1412.41,2329.9 r180 top
U13 "LMH5401IRMSR" RMS0014A 652.3,1165.29 r270 top
U14 "LMH6401IRMZR" RMZ0016A 1047.48,1165.56 r0 top
U15 "OPA376AIDCKT" DCK0005A_N#2 1412.48,910.56 r180 top
U16 "LMC6762AIMX" M08A_N 5152.3,794.25 r0 top
U17 "ADC12DJ3200AAVR" AAV0144A 2401.5,1879.1 r0 top
U18 "LM95233CISD/NOPB" SDA14B 3106.5,3149.82 r0 top
U19 "LMX2594RHAR" RHA0040A 2214.86,6139.82 r90 top
U20 "DS90LV028AQMA" M08A_N 1507.81,5730.52 r90 bottom
U21 "LMX2594RHAR" RHA0040A 2336.76,3678.16 r270 top
U22 "DS90LV028AQMA" M08A_N 3043.8,4087.45 r270 bottom
U23 "LMK00304SQ/NOPB" RTV0032A 3320.29,4975.78 r0 top
U24 "LMK04828" NKD0064A 4591.26,4939.72 r0 top
U25 "LMK61E2-SIAR" SIA0008B 5505.97,5985.84 r90 bottom
U26 "SN74AVC4T774PWR" PW0016A_N 5590.86,10422.98 r0 top
U27 "SN74AVC4T774PWR" PW0016A_N 5024.82,9217.2 r180 top
U28 "SN74LVC1G125DBVR" DBV0005A_N 6185.59,9666.91 r0 top
U29 "SN74AVC4T774PWR" PW0016A_N 5459.82,9253 r0 bottom
U30 "SN74AVC4T774PWR" PW0016A_N 3711.47,6693.22 r180 top
U31 "SN74AVC4T774PWR" PW0016A_N 3714.8,347.22 r180 top
U32 "SN74AVC4T774PWR" PW0016A_N 3711.47,7137.93 r180 top
U33 "SN74AVC4T774PWR" PW0016A_N 3714.8,791.93 r180 top
U34 "FT4232HL-REEL" LQFP64_N 5301.88,9883.97 r180 top
U35 "TLV70233DBVT" DBV0005A_N 6256.59,10017.27 r180 top
U36 "24C65" SOIC127P800X216-8N 5816.21,6921.37 r270 top
U37 "24C65" SOIC127P800X216-8N 5815.4,568.08 r270 top
U38 "TPS259261DRCR" DRC0010J 5004.7,11291.8 r180 top
U39 "TPS82130SILR" SIL0008D_SMD 2934.66,11322.66 r180 bottom
U40 "NFM31PC276B0J3L" Murata_NFM31P#1 2917.93,10838.98 r315 top
U41 "TPS7A8400RGRR" RGR0020A 3254.55,10931.64 r90 top
U42 "TPS82130SILR" SIL0008D_SMD 2067.66,11322.61 r180 bottom
U43 "NFM31PC276B0J3L" Murata_NFM31P#1 2044.1,10839.84 r315 top
U44 "TPS7A8400RGRR" RGR0020A 2380.72,10932.5 r90 top
U45 "TPS82130SILR" SIL0008D_SMD 3783.67,11326.79 r180 bottom
U46 "NFM31PC276B0J3L" Murata_NFM31P#2 396.15,6493.34 r315 top
U47 "TPS7A8400RGRR" RGR0020A 4091.53,10927.63 r90 top
U48 "TPS82130SILR" SIL0008D_SMD 1367.87,11322.83 r180 bottom
U49 "NFM31PC276B0J3L" Murata_NFM31P#1 1310.23,10841.7 r315 top
U50 "TPS7A8300RGRR" RGR0020A 1646.85,10934.36 r90 top
U51 "TPS82130SILR" SIL0008D_SMD 664.55,11324.65 r180 bottom
U52 "NFM31PC276B0J3L" Murata_NFM31P#1 500.89,10844.99 r315 top
U53 "TPS7A3301RGWT" RGW0020A 855.91,10901.1 r90 top
U54 "SN74LVC1G125DBVR" DBV0005A_N 5083.88,10245.97 r180 top
U55 "TCA9534APWR" PW0016A_N 4079.82,6905.51 r0 top
U56 "93LC46BT-I/SN" SOIC-8 5416.88,9226.97 r270 top
U57 "TCA9534APWR" PW0016A_N 4083.15,559.52 r0 top
U58 "TCA9534APWR" PW0016A_N 3546.18,4188.15 r180 top
U59 "BAL-0006SMG" MARKI_BAL-0006SMG 2334.48,8937.21 r180 bottom locked
U60 "BAL-0006SMG" MARKI_BAL-0006SMG 2335.24,7512.98 r0 bottom locked
U61 "BAL-0006SMG" MARKI_BAL-0006SMG 2337.48,2591.59 r180 bottom locked
U62 "BAL-0006SMG" MARKI_BAL-0006SMG 2339.42,1167.02 r0 bottom locked
U63 "SN74LVC1G08DCKR" DCK0005A_N#2 5882.47,3720.1 r180 bottom
U64 "SN74LVC1G08DCKR" DCK0005A_N#2 5886.9,3453.82 r180 bottom
U65 "XLF-192+" DQ1225 1908.92,9102.54 r0 top
U66 "XLF-192+" DQ1225 1908.92,8766.84 r0 top
U67 "XLF-192+" DQ1225 1912.54,7680.46 r0 top
U68 "XLF-192+" DQ1225 1912.54,7344.76 r0 top
U69 "XLF-192+" DQ1225 1912.54,2756.86 r0 top
U70 "XLF-192+" DQ1225 1912.54,2421.16 r0 top
U71 "XLF-192+" DQ1225 1912.54,1337.76 r0 top
U72 "XLF-192+" DQ1225 1912.54,1002.06 r0 top
U73 "DS90LT012AQMF/NOPB" MF05A_N 4111.5,5813 r180 bottom
U74 "NB7V33MMNTXG" QFN16-3x3MM_0_5 5232.63,4644.71 r135 top
U75 "SN74LVC2G53DCU" DCU0008A_N 4144,9254 r180 top
Vtune_TP1 "5002" Keystone5002 2718.66,5613.82 r135 top
Vtune_TP2 "5002" Keystone5002 1857.96,4204.16 r45 top
Y1 "CVHD-950-100.000" OSC_CVHD-950-4 5474.02,5943.56 r270 top
Y2 "ABM3-12.000MHZ-D2Y-T" XTAL_ABM3 5815.88,9698.97 r90 top
ZZ1 "This Assembly Note is for PCB labels only" AssemblyNoteLabel -585.43,9007.45 r0 top
ZZ2 "These assemblies are ESD sensitive, ESD precautions shall be observed." AssemblyNote -668.43,8258.45 r0 top
ZZ3 "These assemblies must be clean and free from flux and all contaminants. Use of no clean flux is not acceptable." AssemblyNote -664.43,8188.45 r0 top
ZZ4 "These assemblies must comply with workmanship standards IPC-A-610 Class 2, unless otherwise specified." AssemblyNote -656.43,8118.45 r0 top

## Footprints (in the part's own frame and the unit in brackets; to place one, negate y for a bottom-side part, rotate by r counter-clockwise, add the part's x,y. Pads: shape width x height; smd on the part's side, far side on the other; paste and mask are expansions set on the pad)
0201#1 [mm] "Data from Kemet datasheet CC101_COM dated 7/28/11"
  rect 0.46x0.42 smd mask+0.048: 1(-0.33,0) 2(0.33,0)
  body extent -0.31,-0.16 0.31,0.16, height 0.26
0201#2 [mm] "Data from Kemet datasheet CC101_COM dated 7/28/11"
  rect 0.46x0.42 smd mask+0.048: 1(-61.384,-75.853) 2(-60.724,-75.853)
  body extent -61.37,-76.02 -60.74,-75.69, height 0.26
0201_033 [mm] "SMD, 2-Leads, Height 0.33mm"
  rect 0.46x0.42 smd mask+0.048: 1(-0.33,0) 2(0.33,0)
  body extent -0.31,-0.16 0.31,0.16, height 0.33
0201_ADC [mil] "Data from Kemet datasheet CC101_COM dated 7/28/11"
  rect 12x12 smd mask+1.9: 1(-12.99,0) 2(12.99,0)
  silkscreen extent -15,-15 15,15, body extent -12,-6 12,6, height 10
0201_adc [mil] "Data from Kemet datasheet CC101_COM dated 7/28/11"
  rect 12x12 smd mask+1.9: 1(-12.99,0) 2(12.99,0)
  silkscreen extent -15,-15 15,15, body extent -12,-6 12,6, height 10
0306#1 [mm] "based on TDK recommendation (similar to Taiyo Yuden and MuRata)"
  rrect29% 0.35x1.6 smd: 1(-0.325,0) 2(0.325,0)
  body extent -0.44,-0.85 0.44,0.85, height 0.6
0306#2 [mm] "based on TDK recommendation (similar to Taiyo Yuden and MuRata)"
  rrect29% 0.35x1.6 smd: 1(-0.318,-0.008) 2(0.332,-0.008)
  body extent -0.44,-0.86 0.45,0.84, height 0.6
0306#3 [mm] "based on TDK recommendation (similar to Taiyo Yuden and MuRata)"
  rrect29% 0.35x1.6 smd: 1(-0.575,0.377) 2(0.075,0.377)
  body extent -0.69,-0.47 0.19,1.23, height 0.6
0402#1 [mm] "0402 from SM-752 data"
  rect 0.8x0.6 smd: 1(-0.6,0) 2(0.6,0)
  silkscreen extent -1.22,-0.52 1.22,0.52, body extent -0.55,-0.3 0.55,0.3, height 0.6
0402#2 [mm] "0402 from SM-752 data"
  rect 0.8x0.6 smd: 1(1.889,-0.076) 2(3.089,-0.076)
  silkscreen extent 1.27,-0.6 3.71,0.44, body extent 1.94,-0.38 3.04,0.22, height 0.6
0402_065 [mm] "0402"
  rect 0.8x0.6 smd: 1(-0.6,0) 2(0.6,0)
  silkscreen extent -1.22,-0.52 1.22,0.52, body extent -0.55,-0.3 0.55,0.3, height 0.65
0402_FILTER [mil]
  rect 15x15 smd: 1(-23.62,0) 2(23.62,0)
  silkscreen extent -48,-20 48,20, body extent -22,-12 22,12, height 24
0402L [mm] "0402 from SM-752 data"
  rect 0.6x0.5 smd: 1(-0.5,0) 2(0.5,0)
  body extent -0.55,-0.3 0.55,0.3, height 0.6
0603 [mm] "0603 from SM-752 data"
  rect 1x0.95 smd: 1(-0.8,0) 2(0.8,0)
  silkscreen extent -1.52,-0.69 1.52,0.69, body extent -0.87,-0.47 0.87,0.47, height 1
"0603_1.6x0.8x0.8mm_Reflow Soldering"#1 [mm]
  rect 1x0.95 smd: 1(-0.8,0) 2(0.8,0)
  silkscreen extent -1.52,-0.69 1.52,0.69, body extent -0.87,-0.47 0.87,0.47, height 1
"0603_1.6x0.8x0.8mm_Reflow Soldering"#2 [mm]
  rect 1x0.95 smd: 1(-0.927,0) 2(0.673,0)
  silkscreen extent -1.65,-0.69 1.4,0.69, body extent -1,-0.47 0.75,0.47, height 1
0603HC [mm] "SMD, 2-Leads, Body 1.8x1.12mm, Lead Spacing 1.28mm"
  rect 0.64x1.02 smd: 1(-0.64,0) 2(0.64,0)
  silkscreen extent -0.18,-0.7 0.18,0.7, body extent -0.9,-0.56 0.9,0.56, height 1.01
0603L [mm] "0603 from SM-752 data"
  rect 0.8x0.85 smd: 1(-0.7,0) 2(0.7,0)
  silkscreen extent -0.07,-0.32 0.07,0.32, body extent -0.87,-0.47 0.87,0.47, height 1
0805 [mm] "0805 from SM-752 data"
  rect 1.3x1.5 smd: 1(-0.85,0) 2(0.85,0)
  silkscreen extent -1.72,-0.97 1.72,0.97, body extent -1.1,-0.72 1.1,0.72, height 1.45
0805_HV [mil] "0805 with 30mil clearance between pads"
  rect 50x63 smd: 1(-40,0) 2(40,0)
  silkscreen extent -74,-40 74,40, body extent -43,-29 43,29, height 57
1206 [mm] "1206 from SM-752 data"
  rect 1.3x1.85 smd: 1(-1.45,0) 2(1.45,0)
  silkscreen extent -2.4,-1.21 2.4,1.21, body extent -1.7,-0.9 1.7,0.9, height 1.35
1206_3.2x1.6x1.6mm [mm]
  rect 1.1x1.6 smd: 1(-1.7,0) 2(1.7,0)
  silkscreen extent -0.9,-1 0.9,1, body extent -1.75,-0.95 1.75,0.95, height 1.8
1206_180 [mm] "1206_180"
  rect 1.1x1.6 smd: 1(-1.7,0) 2(1.7,0)
  silkscreen extent -0.9,-1 0.9,1, body extent -1.75,-0.95 1.75,0.95, height 1.8
1206_190 [mm] "1206_190"
  rect 1.1x1.6 smd: 1(-1.7,0) 2(1.7,0)
  silkscreen extent -0.9,-1 0.9,1, body extent -1.75,-0.95 1.75,0.95, height 1.9
1210_270 [mm] "1210"
  rect 1.3x2.7 smd: 1(-1.45,0) 2(1.45,0)
  silkscreen extent -2.32,-1.57 2.32,1.57, body extent -1.7,-1.35 1.7,1.35, height 2.7
1806_HIGHSPEED [mm] "Wurth recommended land pattern"
  rrect8% 1.25x1.2 smd: 1(-2.125,0) 2(2.125,0)
  silkscreen extent -1.5,-1 1.5,1, body extent -2.25,-0.8 2.25,0.8, height 1.61
1806_HighSpeed [mm] "Wurth recommended land pattern"
  rrect8% 1.25x1.2 smd: 1(-2.125,0) 2(2.125,0)
  silkscreen extent -1.5,-1 1.5,1, body extent -2.25,-0.8 2.25,0.8, height 1.61
3216-18 [mm] "Based on AVX recommendation in http://www.avx.com/download/software/literature/AVX-Footprint-Library.pdf"
  rrect7% 1.4x1.8 smd: 1(-1.3,0) 2(1.3,0)
  silkscreen extent -1.9,-1.13 0.8,1.12, body extent -1.7,-0.9 1.7,0.9, height 1.82
3528-21 [mm] "Medium Density IPC, based on Kemet datasheet 2016-10-20"
  rrect6% 1.8x2.23 smd: 1(-1.46,0) 2(1.46,0)
  silkscreen extent -2.29,-1.5 0.76,1.5, body extent -1.85,-1.5 1.85,1.5, height 2.12
651305142821 [mm] "5 pins"
  rect 0.5x2.25 smd: 1(-1.6,2.8) 2(-0.8,2.8) 3(0,2.8) 4(0.8,2.8) 5(1.6,2.8)
  rect 2x2.5 smd: Shell(-4.45,-2.8) Shell(-4.45,2.7) Shell(4.45,-2.8) Shell(4.45,2.7)
  silkscreen extent -3.85,-5.74 3.85,4.1, body extent -4.95,-5.74 4.95,3.66
AAV0144A [mm] "BGA, 144-Leads, Body 10x10mm, Pitch 0.8mm"
  round 0.4 smd: A1(-4.4,4.4) A2(-3.6,4.4) A3(-2.8,4.4) A4(-2,4.4) A5(-1.2,4.4) A6(-0.4,4.4) A7(0.4,4.4) A8(1.2,4.4) A9(2,4.4) A10(2.8,4.4) A11(3.6,4.4) A12(4.4,4.4) B1(-4.4,3.6) B2(-3.6,3.6) B3(-2.8,3.6) B4(-2,3.6) B5(-1.2,3.6) B6(-0.4,3.6) B7(0.4,3.6) B8(1.2,3.6) B9(2,3.6) B10(2.8,3.6) B11(3.6,3.6) B12(4.4,3.6) C1(-4.4,2.8) C2(-3.6,2.8) C3(-2.8,2.8) C4(-2,2.8) C5(-1.2,2.8) C6(-0.4,2.8) C7(0.4,2.8) C8(1.2,2.8) C9(2,2.8) C10(2.8,2.8) C11(3.6,2.8) C12(4.4,2.8) D1(-4.4,2) D2(-3.6,2) D3(-2.8,2) D4(-2,2) D5(-1.2,2) D6(-0.4,2) D7(0.4,2) D8(1.2,2) D9(2,2) D10(2.8,2) D11(3.6,2) D12(4.4,2) E1(-4.4,1.2) E2(-3.6,1.2) E3(-2.8,1.2) E4(-2,1.2) E5(-1.2,1.2) E6(-0.4,1.2) E7(0.4,1.2) E8(1.2,1.2) E9(2,1.2) E10(2.8,1.2) E11(3.6,1.2) E12(4.4,1.2) F1(-4.4,0.4) F2(-3.6,0.4) F3(-2.8,0.4) F4(-2,0.4) F5(-1.2,0.4) F6(-0.4,0.4) F7(0.4,0.4) F8(1.2,0.4) F9(2,0.4) F10(2.8,0.4) F11(3.6,0.4) F12(4.4,0.4) G1(-4.4,-0.4) G2(-3.6,-0.4) G3(-2.8,-0.4) G4(-2,-0.4) G5(-1.2,-0.4) G6(-0.4,-0.4) G7(0.4,-0.4) G8(1.2,-0.4) G9(2,-0.4) G10(2.8,-0.4) G11(3.6,-0.4) G12(4.4,-0.4) H1(-4.4,-1.2) H2(-3.6,-1.2) H3(-2.8,-1.2) H4(-2,-1.2) H5(-1.2,-1.2) H6(-0.4,-1.2) H7(0.4,-1.2) H8(1.2,-1.2) H9(2,-1.2) H10(2.8,-1.2) H11(3.6,-1.2) H12(4.4,-1.2) J1(-4.4,-2) J2(-3.6,-2) J3(-2.8,-2) J4(-2,-2) J5(-1.2,-2) J6(-0.4,-2) J7(0.4,-2) J8(1.2,-2) J9(2,-2) J10(2.8,-2) J11(3.6,-2) J12(4.4,-2) K1(-4.4,-2.8) K2(-3.6,-2.8) K3(-2.8,-2.8) K4(-2,-2.8) K5(-1.2,-2.8) K6(-0.4,-2.8) K7(0.4,-2.8) K8(1.2,-2.8) K9(2,-2.8) K10(2.8,-2.8) K11(3.6,-2.8) K12(4.4,-2.8) L1(-4.4,-3.6) L2(-3.6,-3.6) L3(-2.8,-3.6) L4(-2,-3.6) L5(-1.2,-3.6) L6(-0.4,-3.6) L7(0.4,-3.6) L8(1.2,-3.6) L9(2,-3.6) L10(2.8,-3.6) L11(3.6,-3.6) L12(4.4,-3.6) M1(-4.4,-4.4) M2(-3.6,-4.4) M3(-2.8,-4.4) M4(-2,-4.4) M5(-1.2,-4.4) M6(-0.4,-4.4) M7(0.4,-4.4) M8(1.2,-4.4) M9(2,-4.4) M10(2.8,-4.4) M11(3.6,-4.4) M12(4.4,-4.4)
  silkscreen extent -5.4,-5.07 5.07,5.17, body extent -5,-5 5,5, height 1.77
ASP-184330-01#1 [mil]
  round 25 smd paste+5 mask+2: A1(975,225) A2(925,225) A3(875,225) A4(825,225) A5(775,225) A6(725,225) A7(675,225) A8(625,225) A9(575,225) A10(525,225) A11(475,225) A12(425,225) A13(375,225) A14(325,225) A15(275,225) A16(225,225) A17(175,225) A18(125,225) A19(75,225) A20(25,225) A21(-25,225) A22(-75,225) A23(-125,225) A24(-175,225) A25(-225,225) A26(-275,225) A27(-325,225) A28(-375,225) A29(-425,225) A30(-475,225) A31(-525,225) A32(-575,225) A33(-625,225) A34(-675,225) A35(-725,225) A36(-775,225) A37(-825,225) A38(-875,225) A39(-925,225) A40(-975,225) B1(975,175) B2(925,175) B3(875,175) B4(825,175) B5(775,175) B6(725,175) B7(675,175) B8(625,175) B9(575,175) B10(525,175) B11(475,175) B12(425,175) B13(375,175) B14(325,175) B15(275,175) B16(225,175) B17(175,175) B18(125,175) B19(75,175) B20(25,175) B21(-25,175) B22(-75,175) B23(-125,175) B24(-175,175) B25(-225,175) B26(-275,175) B27(-325,175) B28(-375,175) B29(-425,175) B30(-475,175) B31(-525,175) B32(-575,175) B33(-625,175) B34(-675,175) B35(-725,175) B36(-775,175) B37(-825,175) B38(-875,175) B39(-925,175) B40(-975,175) C1(975,125) C2(925,125) C3(875,125) C4(825,125) C5(775,125) C6(725,125) C7(675,125) C8(625,125) C9(575,125) C10(525,125) C11(475,125) C12(425,125) C13(375,125) C14(325,125) C15(275,125) C16(225,125) C17(175,125) C18(125,125) C19(75,125) C20(25,125) C21(-25,125) C22(-75,125) C23(-125,125) C24(-175,125) C25(-225,125) C26(-275,125) C27(-325,125) C28(-375,125) C29(-425,125) C30(-475,125) C31(-525,125) C32(-575,125) C33(-625,125) C34(-675,125) C35(-725,125) C36(-775,125) C37(-825,125) C38(-875,125) C39(-925,125) C40(-975,125) D1(975,75) D2(925,75) D3(875,75) D4(825,75) D5(775,75) D6(725,75) D7(675,75) D8(625,75) D9(575,75) D10(525,75) D11(475,75) D12(425,75) D13(375,75) D14(325,75) D15(275,75) D16(225,75) D17(175,75) D18(125,75) D19(75,75) D20(25,75) D21(-25,75) D22(-75,75) D23(-125,75) D24(-175,75) D25(-225,75) D26(-275,75) D27(-325,75) D28(-375,75) D29(-425,75) D30(-475,75) D31(-525,75) D32(-575,75) D33(-625,75) D34(-675,75) D35(-725,75) D36(-775,75) D37(-825,75) D38(-875,75) D39(-925,75) D40(-975,75) E1(975,25) E2(925,25) E3(875,25) E4(825,25) E5(775,25) E6(725,25) E7(675,25) E8(625,25) E9(575,25) E10(525,25) E11(475,25) E12(425,25) E13(375,25) E14(325,25) E15(275,25) E16(225,25) E17(175,25) E18(125,25) E19(75,25) E20(25,25) E21(-25,25) E22(-75,25) E23(-125,25) E24(-175,25) E25(-225,25) E26(-275,25) E27(-325,25) E28(-375,25) E29(-425,25) E30(-475,25) E31(-525,25) E32(-575,25) E33(-625,25) E34(-675,25) E35(-725,25) E36(-775,25) E37(-825,25) E38(-875,25) E39(-925,25) E40(-975,25) F1(975,-25) F2(925,-25) F3(875,-25) F4(825,-25) F5(775,-25) F6(725,-25) F7(675,-25) F8(625,-25) F9(575,-25) F10(525,-25) F11(475,-25) F12(425,-25) F13(375,-25) F14(325,-25) F15(275,-25) F16(225,-25) F17(175,-25) F18(125,-25) F19(75,-25) F20(25,-25) F21(-25,-25) F22(-75,-25) F23(-125,-25) F24(-175,-25) F25(-225,-25) F26(-275,-25) F27(-325,-25) F28(-375,-25) F29(-425,-25) F30(-475,-25) F31(-525,-25) F32(-575,-25) F33(-625,-25) F34(-675,-25) F35(-725,-25) F36(-775,-25) F37(-825,-25) F38(-875,-25) F39(-925,-25) F40(-975,-25) G1(975,-75) G2(925,-75) G3(875,-75) G4(825,-75) G5(775,-75) G6(725,-75) G7(675,-75) G8(625,-75) G9(575,-75) G10(525,-75) G11(475,-75) G12(425,-75) G13(375,-75) G14(325,-75) G15(275,-75) G16(225,-75) G17(175,-75) G18(125,-75) G19(75,-75) G20(25,-75) G21(-25,-75) G22(-75,-75) G23(-125,-75) G24(-175,-75) G25(-225,-75) G26(-275,-75) G27(-325,-75) G28(-375,-75) G29(-425,-75) G30(-475,-75) G31(-525,-75) G32(-575,-75) G33(-625,-75) G34(-675,-75) G35(-725,-75) G36(-775,-75) G37(-825,-75) G38(-875,-75) G39(-925,-75) G40(-975,-75) H1(975,-125) H2(925,-125) H3(875,-125) H4(825,-125) H5(775,-125) H6(725,-125) H7(675,-125) H8(625,-125) H9(575,-125) H10(525,-125) H11(475,-125) H12(425,-125) H13(375,-125) H14(325,-125) H15(275,-125) H16(225,-125) H17(175,-125) H18(125,-125) H19(75,-125) H20(25,-125) H21(-25,-125) H22(-75,-125) H23(-125,-125) H24(-175,-125) H25(-225,-125) H26(-275,-125) H27(-325,-125) H28(-375,-125) H29(-425,-125) H30(-475,-125) H31(-525,-125) H32(-575,-125) H33(-625,-125) H34(-675,-125) H35(-725,-125) H36(-775,-125) H37(-825,-125) H38(-875,-125) H39(-925,-125) H40(-975,-125) J1(975,-175) J2(925,-175) J3(875,-175) J4(825,-175) J5(775,-175) J6(725,-175) J7(675,-175) J8(625,-175) J9(575,-175) J10(525,-175) J11(475,-175) J12(425,-175) J13(375,-175) J14(325,-175) J15(275,-175) J16(225,-175) J17(175,-175) J18(125,-175) J19(75,-175) J20(25,-175) J21(-25,-175) J22(-75,-175) J23(-125,-175) J24(-175,-175) J25(-225,-175) J26(-275,-175) J27(-325,-175) J28(-375,-175) J29(-425,-175) J30(-475,-175) J31(-525,-175) J32(-575,-175) J33(-625,-175) J34(-675,-175) J35(-725,-175) J36(-775,-175) J37(-825,-175) J38(-875,-175) J39(-925,-175) J40(-975,-175) K1(975,-225) K2(925,-225) K3(875,-225) K4(825,-225) K5(775,-225) K6(725,-225) K7(675,-225) K8(625,-225) K9(575,-225) K10(525,-225) K11(475,-225) K12(425,-225) K13(375,-225) K14(325,-225) K15(275,-225) K16(225,-225) K17(175,-225) K18(125,-225) K19(75,-225) K20(25,-225) K21(-25,-225) K22(-75,-225) K23(-125,-225) K24(-175,-225) K25(-225,-225) K26(-275,-225) K27(-325,-225) K28(-375,-225) K29(-425,-225) K30(-475,-225) K31(-525,-225) K32(-575,-225) K33(-625,-225) K34(-675,-225) K35(-725,-225) K36(-775,-225) K37(-825,-225) K38(-875,-225) K39(-925,-225) K40(-975,-225) L1(975,-275) L2(925,-275) L3(875,-275) L4(825,-275) L5(775,-275) L6(725,-275) L7(675,-275) L8(625,-275) L9(575,-275) L10(525,-275) L11(475,-275) L12(425,-275) L13(375,-275) L14(325,-275) L15(275,-275) L16(225,-275) L17(175,-275) L18(125,-275) L19(75,-275) L20(25,-275) L21(-25,-275) L22(-75,-275) L23(-125,-275) L24(-175,-275) L25(-225,-275) L26(-275,-275) L27(-325,-275) L28(-375,-275) L29(-425,-275) L30(-475,-275) L31(-525,-275) L32(-575,-275) L33(-625,-275) L34(-675,-275) L35(-725,-275) L36(-775,-275) L37(-825,-275) L38(-875,-275) L39(-925,-275) L40(-975,-275) M1(975,-325) M2(925,-325) M3(875,-325) M4(825,-325) M5(775,-325) M6(725,-325) M7(675,-325) M8(625,-325) M9(575,-325) M10(525,-325) M11(475,-325) M12(425,-325) M13(375,-325) M14(325,-325) M15(275,-325) M16(225,-325) M17(175,-325) M18(125,-325) M19(75,-325) M20(25,-325) M21(-25,-325) M22(-75,-325) M23(-125,-325) M24(-175,-325) M25(-225,-325) M26(-275,-325) M27(-325,-325) M28(-375,-325) M29(-425,-325) M30(-475,-325) M31(-525,-325) M32(-575,-325) M33(-625,-325) M34(-675,-325) M35(-725,-325) M36(-775,-325) M37(-825,-325) M38(-875,-325) M39(-925,-325) M40(-975,-325) Y1(975,325) Y2(925,325) Y3(875,325) Y4(825,325) Y5(775,325) Y6(725,325) Y7(675,325) Y8(625,325) Y9(575,325) Y10(525,325) Y11(475,325) Y12(425,325) Y13(375,325) Y14(325,325) Y15(275,325) Y16(225,325) Y17(175,325) Y18(125,325) Y19(75,325) Y20(25,325) Y21(-25,325) Y22(-75,325) Y23(-125,325) Y24(-175,325) Y25(-225,325) Y26(-275,325) Y27(-325,325) Y28(-375,325) Y29(-425,325) Y30(-475,325) Y31(-525,325) Y32(-575,325) Y33(-625,325) Y34(-675,325) Y35(-725,325) Y36(-775,325) Y37(-825,325) Y38(-875,325) Y39(-925,325) Y40(-975,325) Z1(975,275) Z2(925,275) Z3(875,275) Z4(825,275) Z5(775,275) Z6(725,275) Z7(675,275) Z8(625,275) Z9(575,275) Z10(525,275) Z11(475,275) Z12(425,275) Z13(375,275) Z14(325,275) Z15(275,275) Z16(225,275) Z17(175,275) Z18(125,275) Z19(75,275) Z20(25,275) Z21(-25,275) Z22(-75,275) Z23(-125,275) Z24(-175,275) Z25(-225,275) Z26(-275,275) Z27(-325,275) Z28(-375,275) Z29(-425,275) Z30(-475,275) Z31(-525,275) Z32(-575,275) Z33(-625,275) Z34(-675,275) Z35(-725,275) Z36(-775,275) Z37(-825,275) Z38(-875,275) Z39(-925,275) Z40(-975,275)
  round 50 hole 50 unplated mask+10: MH1(1070.5,0) MH2(-1070.5,-120)
  silkscreen extent -1118,-409 1153,409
